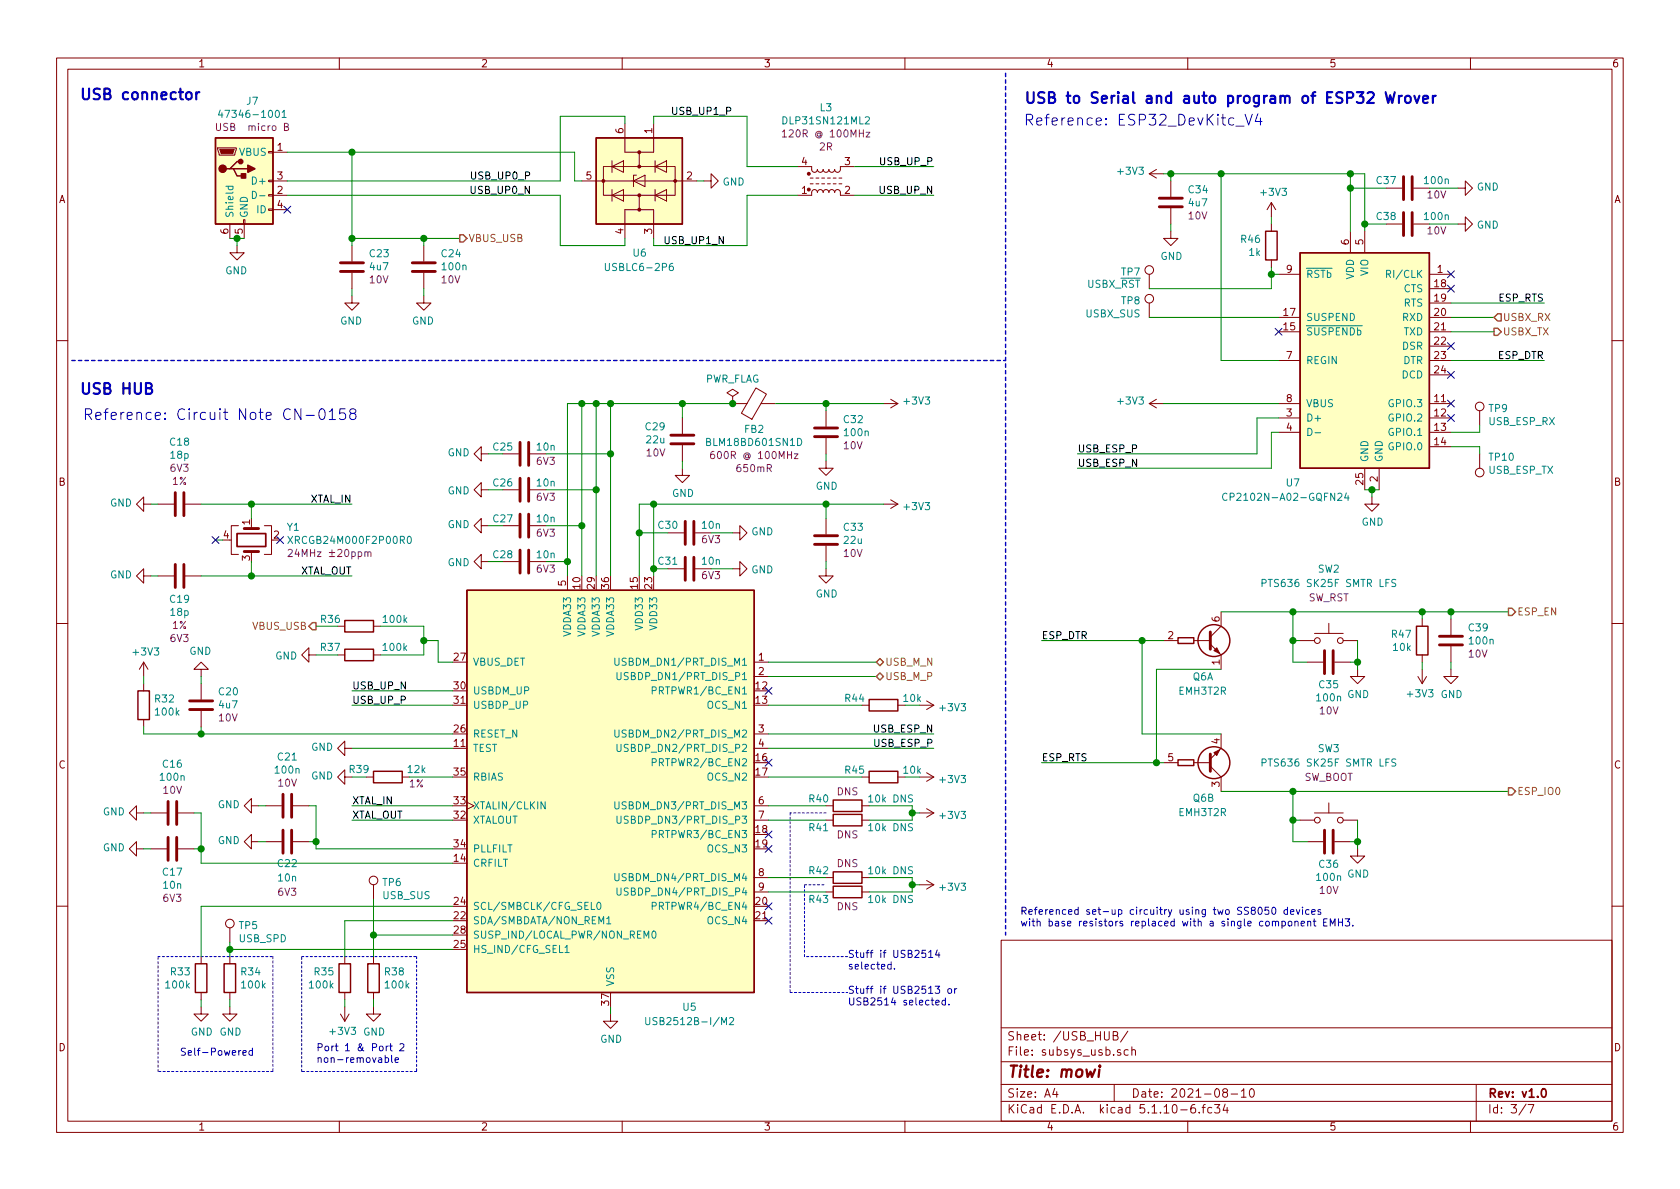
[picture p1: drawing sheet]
<svg xmlns="http://www.w3.org/2000/svg" width="297mm" height="210mm" viewBox="0 0 297 210" stroke-linecap="round" stroke-linejoin="round" font-family="sans-serif">
<defs><g id="words">
<text font-size="2.8" fill="#840000" x="178" y="190.5">Title: mowi</text>
<g font-size="2.7" fill="#0000c2">
<text x="14" y="17.7">USB connector</text>
<text x="181" y="18.3">USB to Serial and auto program of ESP32 Wrover</text>
<text x="181" y="22.2">Reference: ESP32_DevKitc_V4</text>
<text x="14" y="69.7">USB HUB</text>
<text x="14.6" y="74.3">Reference: Circuit Note CN-0158</text>
</g>
<g font-size="2.1" fill="#840000">
<text x="178" y="184">Sheet: /USB_HUB/</text>
<text x="178" y="186.7">File: subsys_usb.sch</text>
<text x="178" y="196.9">KiCad E.D.A. kicad 5.1.10-6.fc34</text>
<text x="178" y="194.1">Size: A4</text>
<text x="200" y="194.1">Date: 2021-08-10</text>
<text x="263" y="194.1">Rev: v1.0</text>
<text x="263" y="196.9">Id: 3/7</text>
</g>
<g font-size="1.8" fill="#840000">
<text x="35" y="11.9">1</text>
<text x="85" y="11.9">2</text>
<text x="135" y="11.9">3</text>
<text x="185" y="11.9">4</text>
<text x="235" y="11.9">5</text>
<text x="285" y="11.9">6</text>
<text x="110.2" y="23.6" transform="rotate(-90 110.2 23.6)">6</text>
<text x="115.3" y="23.6" transform="rotate(-90 115.3 23.6)">1</text>
<text x="49" y="26.7">1</text>
<text x="141.8" y="29.2">4</text>
<text x="149.4" y="29.2">3</text>
<text x="10.4" y="35.9">A</text>
<text x="49" y="34.3">2</text>
<text x="49" y="31.7">3</text>
<text x="103.7" y="31.7">5</text>
<text x="121.4" y="31.7">2</text>
<text x="141.8" y="34.3">1</text>
<text x="149.4" y="34.3">2</text>
<text x="285.4" y="35.9">A</text>
<text x="40.4" y="41.4" transform="rotate(-90 40.4 41.4)">6</text>
<text x="42.9" y="41.4" transform="rotate(-90 42.9 41.4)">5</text>
<text x="49" y="36.8">4</text>
<text x="110.2" y="41.4" transform="rotate(-90 110.2 41.4)">4</text>
<text x="115.3" y="41.4" transform="rotate(-90 115.3 41.4)">3</text>
<text x="238.5" y="43.3" transform="rotate(-90 238.5 43.3)">6</text>
<text x="241" y="43.3" transform="rotate(-90 241 43.3)">5</text>
<text x="227.5" y="48.3">9</text>
<text x="253.7" y="50.8">18</text>
<text x="253.7" y="53.3">19</text>
<text x="254.2" y="48.3">1</text>
<text x="227" y="58.4">15</text>
<text x="227" y="55.9">17</text>
<text x="253.7" y="55.9">20</text>
<text x="253.7" y="58.4">21</text>
<text x="227.5" y="63.5">7</text>
<text x="253.7" y="61">22</text>
<text x="253.7" y="63.5">23</text>
<text x="227.5" y="71.1">8</text>
<text x="253.7" y="71.1">11</text>
<text x="253.7" y="66">24</text>
<text x="227.5" y="73.7">3</text>
<text x="227.5" y="76.2">4</text>
<text x="253.7" y="73.7">12</text>
<text x="253.7" y="76.2">13</text>
<text x="253.7" y="78.7">14</text>
<text x="10.4" y="85.9">B</text>
<text x="241" y="85.7" transform="rotate(-90 241 85.7)">25</text>
<text x="243.6" y="85.2" transform="rotate(-90 243.6 85.2)">2</text>
<text x="285.4" y="85.9">B</text>
<text x="39.5" y="95.2">4</text>
<text x="44.2" y="92.8" transform="rotate(-90 44.2 92.8)">1</text>
<text x="48.4" y="95.2">2</text>
<text x="44.2" y="99.2" transform="rotate(-90 44.2 99.2)">3</text>
<text x="100.1" y="103.6" transform="rotate(-90 100.1 103.6)">5</text>
<text x="102.6" y="104.1" transform="rotate(-90 102.6 104.1)">10</text>
<text x="105.2" y="104.1" transform="rotate(-90 105.2 104.1)">29</text>
<text x="107.7" y="104.1" transform="rotate(-90 107.7 104.1)">36</text>
<text x="112.8" y="104.1" transform="rotate(-90 112.8 104.1)">15</text>
<text x="115.3" y="104.1" transform="rotate(-90 115.3 104.1)">23</text>
<text x="206.5" y="113">2</text>
<text x="215.6" y="110" transform="rotate(-90 215.6 110)">6</text>
<text x="80.3" y="116.8">27</text>
<text x="134.1" y="116.8">1</text>
<text x="134.1" y="119.4">2</text>
<text x="215.6" y="117.6" transform="rotate(-90 215.6 117.6)">1</text>
<text x="80.3" y="121.9">30</text>
<text x="80.3" y="124.5">31</text>
<text x="133.7" y="121.9">12</text>
<text x="133.7" y="124.5">13</text>
<text x="80.3" y="129.5">26</text>
<text x="134.1" y="129.5">3</text>
<text x="215.6" y="131.5" transform="rotate(-90 215.6 131.5)">4</text>
<text x="10.4" y="135.9">C</text>
<text x="80.3" y="132.1">11</text>
<text x="80.3" y="137.2">35</text>
<text x="133.7" y="134.6">16</text>
<text x="133.7" y="137.2">17</text>
<text x="134.1" y="132.1">4</text>
<text x="206.5" y="134.6">5</text>
<text x="285.4" y="135.9">C</text>
<text x="80.3" y="142.2">33</text>
<text x="134.1" y="142.2">6</text>
<text x="215.6" y="139.2" transform="rotate(-90 215.6 139.2)">3</text>
<text x="80.3" y="144.8">32</text>
<text x="80.3" y="149.9">34</text>
<text x="133.7" y="147.3">18</text>
<text x="133.7" y="149.9">19</text>
<text x="134.1" y="144.8">7</text>
<text x="80.3" y="152.4">14</text>
<text x="134.1" y="154.9">8</text>
<text x="80.3" y="160">24</text>
<text x="133.7" y="160">20</text>
<text x="134.1" y="157.5">9</text>
<text x="80.3" y="162.6">22</text>
<text x="80.3" y="167.6">25</text>
<text x="80.3" y="165.1">28</text>
<text x="133.7" y="162.6">21</text>
<text x="107.7" y="177.7" transform="rotate(-90 107.7 177.7)">37</text>
<text x="10.4" y="185.9">D</text>
<text x="285.4" y="185.9">D</text>
<text x="35" y="199.9">1</text>
<text x="85" y="199.9">2</text>
<text x="135" y="199.9">3</text>
<text x="185" y="199.9">4</text>
<text x="235" y="199.9">5</text>
<text x="285" y="199.9">6</text>
</g>
<g font-size="1.8" fill="#840084">
<text x="39" y="23.2">USB micro B</text>
<text x="139.3" y="24.3">120R @ 100MHz</text>
<text x="144.9" y="26.6">2R</text>
<text x="252.4" y="35.1">10V</text>
<text x="210.2" y="38.8">10V</text>
<text x="252.4" y="41.4">10V</text>
<text x="65.4" y="50.1">10V</text>
<text x="78.1" y="50.1">10V</text>
<text x="30.2" y="83.4">6V3</text>
<text x="94.9" y="82.2">6V3</text>
<text x="114.4" y="80.7">10V</text>
<text x="126.6" y="81.2">600R @ 100MHz</text>
<text x="130.5" y="83.5">650mR</text>
<text x="149.2" y="79.4">10V</text>
<text x="30.5" y="85.7">1%</text>
<text x="94.9" y="88.6">6V3</text>
<text x="94.9" y="94.9">6V3</text>
<text x="51.9" y="98.5">24MHz ±20ppm</text>
<text x="94.9" y="101.3">6V3</text>
<text x="124.2" y="96.1">6V3</text>
<text x="149.2" y="98.5">10V</text>
<text x="124.2" y="102.4">6V3</text>
<text x="231.3" y="106.3">SW_RST</text>
<text x="30.2" y="113.5">6V3</text>
<text x="30.5" y="111.2">1%</text>
<text x="259.7" y="116.3">10V</text>
<text x="38.7" y="127.6">10V</text>
<text x="233.4" y="126.3">10V</text>
<text x="28.9" y="140.4">10V</text>
<text x="49.2" y="139.1">10V</text>
<text x="72.4" y="139.2">1%</text>
<text x="148" y="140.6">DNS</text>
<text x="230.5" y="138.1">SW_BOOT</text>
<text x="148" y="148.3">DNS</text>
<text x="148" y="153.3">DNS</text>
<text x="28.9" y="159.5">6V3</text>
<text x="49.2" y="158.4">6V3</text>
<text x="148" y="161">DNS</text>
<text x="233.4" y="158.1">10V</text>
</g>
<g font-size="1.8" fill="#008484">
<text x="39.9" y="20.8">47346-1001</text>
<text x="43.7" y="18.5">J7</text>
<text x="138.8" y="22">DLP31SN121ML2</text>
<text x="145" y="19.7">L3</text>
<text x="42.3" y="27.6">VBUS</text>
<text x="44.9" y="32.6">D+</text>
<text x="127.8" y="32.8">GND</text>
<text x="197.8" y="30.9">+3V3</text>
<text x="210.2" y="34.2">C34</text>
<text x="223.1" y="34.6">+3V3</text>
<text x="243.5" y="32.6">C37</text>
<text x="252" y="32.6">100n</text>
<text x="261.1" y="33.7">GND</text>
<text x="41.3" y="38.6" transform="rotate(-90 41.3 38.6)">Shield</text>
<text x="43.8" y="38.6" transform="rotate(-90 43.8 38.6)">GND</text>
<text x="45.5" y="37.7">ID</text>
<text x="210.3" y="36.5">4u7</text>
<text x="243.5" y="38.9">C38</text>
<text x="252" y="38.9">100n</text>
<text x="261.1" y="40.4">GND</text>
<text x="65.4" y="45.5">C23</text>
<text x="65.5" y="47.8">4u7</text>
<text x="78.1" y="45.5">C24</text>
<text x="78.3" y="47.8">100n</text>
<text x="107.6" y="47.9">USBLC6-2P6</text>
<text x="112" y="45.4">U6</text>
<text x="205.2" y="46">GND</text>
<text x="219.5" y="42.9">R46</text>
<text x="220.9" y="45.3">1k</text>
<text x="39.8" y="48.5">GND</text>
<text x="192.2" y="50.9">USBX_RST</text>
<text x="198.3" y="53.8">TP8</text>
<text x="198.3" y="48.7">TP7</text>
<text x="230.9" y="49.1">RSTb</text>
<text x="239.4" y="49.4" transform="rotate(-90 239.4 49.4)">VDD</text>
<text x="241.9" y="48.8" transform="rotate(-90 241.9 48.8)">VIO</text>
<text x="245.8" y="49.1">RI/CLK</text>
<text x="248.2" y="51.7">CTS</text>
<text x="60.1" y="57.4">GND</text>
<text x="72.8" y="57.4">GND</text>
<text x="192" y="56.1">USBX_SUS</text>
<text x="230.9" y="59.3">SUSPENDb</text>
<text x="230.9" y="56.8">SUSPEND</text>
<text x="248" y="56.8">RXD</text>
<text x="248.2" y="54.2">RTS</text>
<text x="248.2" y="59.3">TXD</text>
<text x="230.9" y="64.4">REGIN</text>
<text x="248" y="61.8">DSR</text>
<text x="248.1" y="64.4">DTR</text>
<text x="124.6" y="67.7">PWR_FLAG</text>
<text x="160" y="71.5">+3V3</text>
<text x="197.8" y="71.5">+3V3</text>
<text x="247.9" y="66.9">DCD</text>
<text x="114.2" y="76.1">C29</text>
<text x="131.7" y="76.5">FB2</text>
<text x="149.3" y="74.8">C32</text>
<text x="149.4" y="77.1">100n</text>
<text x="230.9" y="74.5">D+</text>
<text x="230.9" y="72">VBUS</text>
<text x="245.8" y="72">GPIO.3</text>
<text x="245.8" y="74.5">GPIO.2</text>
<text x="245.8" y="77.1">GPIO.1</text>
<text x="263.2" y="75.2">USB_ESP_RX</text>
<text x="263.3" y="72.9">TP9</text>
<text x="30.1" y="78.8">C18</text>
<text x="30.2" y="81.1">18p</text>
<text x="79.1" y="80.7">GND</text>
<text x="87.3" y="79.7">C25</text>
<text x="95" y="79.7">10n</text>
<text x="114.4" y="78.4">22u</text>
<text x="125.3" y="78.9">BLM18BD601SN1D</text>
<text x="241.9" y="81.8" transform="rotate(-90 241.9 81.8)">GND</text>
<text x="244.5" y="81.8" transform="rotate(-90 244.5 81.8)">GND</text>
<text x="245.8" y="79.6">GPIO.0</text>
<text x="263.2" y="83.8">USB_ESP_TX</text>
<text x="263.4" y="81.5">TP10</text>
<text x="19.5" y="89.6">GND</text>
<text x="79.1" y="87.4">GND</text>
<text x="87.3" y="86">C26</text>
<text x="95" y="86">10n</text>
<text x="118.8" y="87.9">GND</text>
<text x="144.2" y="86.6">GND</text>
<text x="217.8" y="88.6">CP2102N-A02-GQFN24</text>
<text x="227.5" y="86">U7</text>
<text x="50.8" y="93.9">Y1</text>
<text x="79.1" y="93.4">GND</text>
<text x="87.3" y="92.4">C27</text>
<text x="95" y="92.4">10n</text>
<text x="116.5" y="93.5">C30</text>
<text x="124.2" y="93.5">10n</text>
<text x="132.8" y="94.7">GND</text>
<text x="149.3" y="93.9">C33</text>
<text x="160" y="90.2">+3V3</text>
<text x="240.7" y="93">GND</text>
<text x="51.7" y="96.2">XRCGB24M000F2P00R0</text>
<text x="79.1" y="100.1">GND</text>
<text x="87.3" y="98.7">C28</text>
<text x="95" y="98.7">10n</text>
<text x="116.5" y="99.9">C31</text>
<text x="124.2" y="99.9">10n</text>
<text x="132.8" y="101.4">GND</text>
<text x="149.3" y="96.2">22u</text>
<text x="233" y="101.3">SW2</text>
<text x="19.5" y="102.3">GND</text>
<text x="30.1" y="106.6">C19</text>
<text x="144.2" y="105.7">GND</text>
<text x="224.1" y="103.8">PTS636 SK25F SMTR LFS</text>
<text x="30.2" y="108.9">18p</text>
<text x="56.8" y="110.2">R36</text>
<text x="67.9" y="110.2">100k</text>
<text x="101" y="112.4" transform="rotate(-90 101 112.4)">VDDA33</text>
<text x="103.5" y="112.4" transform="rotate(-90 103.5 112.4)">VDDA33</text>
<text x="106" y="112.4" transform="rotate(-90 106 112.4)">VDDA33</text>
<text x="108.6" y="112.4" transform="rotate(-90 108.6 112.4)">VDDA33</text>
<text x="113.7" y="111.1" transform="rotate(-90 113.7 111.1)">VDD33</text>
<text x="116.2" y="111.1" transform="rotate(-90 116.2 111.1)">VDD33</text>
<text x="246.1" y="112.8">R47</text>
<text x="259.7" y="111.7">C39</text>
<text x="259.9" y="114">100n</text>
<text x="23.7" y="115.9">+3V3</text>
<text x="33.5" y="115.8">GND</text>
<text x="48.7" y="116.6">GND</text>
<text x="56.8" y="115.1">R37</text>
<text x="67.9" y="115.1">100k</text>
<text x="83.6" y="117.7">VBUS_DET</text>
<text x="109.9" y="117.7">USBDM_DN1/PRT_DIS_M1</text>
<text x="246.4" y="115.1">10k</text>
<text x="27.5" y="124.2">R32</text>
<text x="38.8" y="123">C20</text>
<text x="38.8" y="125.3">4u7</text>
<text x="83.6" y="122.8">USBDM_UP</text>
<text x="83.6" y="125.3">USBDP_UP</text>
<text x="110.5" y="120.3">USBDP_DN1/PRT_DIS_P1</text>
<text x="116.2" y="122.8">PRTPWR1/BC_EN1</text>
<text x="125.2" y="125.3">OCS_N1</text>
<text x="149.5" y="124.1">R44</text>
<text x="166.3" y="125.8">+3V3</text>
<text x="208.5" y="122.9">EMH3T2R</text>
<text x="210.9" y="120.3">Q6A</text>
<text x="232.9" y="124">100n</text>
<text x="233.3" y="121.7">C35</text>
<text x="238.2" y="123.4">GND</text>
<text x="249" y="123.3">+3V3</text>
<text x="254.7" y="123.4">GND</text>
<text x="27.6" y="126.5">100k</text>
<text x="83.6" y="130.4">RESET_N</text>
<text x="109.9" y="130.4">USBDM_DN2/PRT_DIS_M2</text>
<text x="28.9" y="135.8">C16</text>
<text x="48.8" y="136.8">100n</text>
<text x="49.2" y="134.5">C21</text>
<text x="55" y="137.8">GND</text>
<text x="55" y="132.8">GND</text>
<text x="61.8" y="136.7">R39</text>
<text x="72.2" y="136.7">12k</text>
<text x="83.6" y="133">TEST</text>
<text x="110.5" y="133">USBDP_DN2/PRT_DIS_P2</text>
<text x="116.2" y="135.5">PRTPWR2/BC_EN2</text>
<text x="149.5" y="136.8">R45</text>
<text x="224.1" y="135.6">PTS636 SK25F SMTR LFS</text>
<text x="233" y="133">SW3</text>
<text x="28.5" y="138.1">100n</text>
<text x="38.5" y="142.9">GND</text>
<text x="83.6" y="143.1">XTALIN/CLKIN</text>
<text x="83.6" y="138">RBIAS</text>
<text x="109.9" y="143.1">USBDM_DN3/PRT_DIS_M3</text>
<text x="125.2" y="138">OCS_N2</text>
<text x="143.1" y="141.9">R40</text>
<text x="153.9" y="141.9">10k DNS</text>
<text x="166.3" y="138.5">+3V3</text>
<text x="211" y="141.8">Q6B</text>
<text x="18.2" y="144.2">GND</text>
<text x="38.5" y="149.3">GND</text>
<text x="83.6" y="145.7">XTALOUT</text>
<text x="110.5" y="145.7">USBDP_DN3/PRT_DIS_P3</text>
<text x="116.2" y="148.2">PRTPWR3/BC_EN3</text>
<text x="143.1" y="147">R41</text>
<text x="153.9" y="147">10k DNS</text>
<text x="166.3" y="144.8">+3V3</text>
<text x="208.5" y="144.3">EMH3T2R</text>
<text x="18.2" y="150.5">GND</text>
<text x="28.9" y="154.9">C17</text>
<text x="49.2" y="153.3">C22</text>
<text x="49.3" y="155.9">10n</text>
<text x="83.6" y="153.3">CRFILT</text>
<text x="83.6" y="150.7">PLLFILT</text>
<text x="109.9" y="155.8">USBDM_DN4/PRT_DIS_M4</text>
<text x="125.2" y="150.7">OCS_N3</text>
<text x="143.1" y="154.6">R42</text>
<text x="153.9" y="154.6">10k DNS</text>
<text x="232.9" y="155.8">100n</text>
<text x="233.3" y="153.5">C36</text>
<text x="238.2" y="155.2">GND</text>
<text x="29" y="157.2">10n</text>
<text x="67.7" y="156.7">TP6</text>
<text x="67.7" y="159">USB_SUS</text>
<text x="83.6" y="160.9">SCL/SMBCLK/CFG_SEL0</text>
<text x="110.5" y="158.4">USBDP_DN4/PRT_DIS_P4</text>
<text x="116.2" y="160.9">PRTPWR4/BC_EN4</text>
<text x="143.1" y="159.7">R43</text>
<text x="153.9" y="159.7">10k DNS</text>
<text x="166.3" y="157.5">+3V3</text>
<text x="42.3" y="164.3">TP5</text>
<text x="42.3" y="166.6">USB_SPD</text>
<text x="83.6" y="163.4">SDA/SMBDATA/NON_REM1</text>
<text x="83.6" y="166">SUSP_IND/LOCAL_PWR/NON_REM0</text>
<text x="125.2" y="163.4">OCS_N4</text>
<text x="30.3" y="172.5">R33</text>
<text x="42.7" y="172.5">R34</text>
<text x="55.7" y="172.5">R35</text>
<text x="68.1" y="172.5">R38</text>
<text x="83.6" y="168.5">HS_IND/CFG_SEL1</text>
<text x="29.4" y="174.8">100k</text>
<text x="42.8" y="174.8">100k</text>
<text x="54.8" y="174.8">100k</text>
<text x="68.2" y="174.8">100k</text>
<text x="108.6" y="174.5" transform="rotate(-90 108.6 174.5)">VSS</text>
<text x="120.8" y="178.7">U5</text>
<text x="33.7" y="183.1">GND GND</text>
<text x="58.5" y="183">+3V3</text>
<text x="64.2" y="183.1">GND</text>
<text x="106.1" y="184.4">GND</text>
<text x="115.4" y="181.3">USB2512B-I/M2</text>
</g>
<g font-size="1.8">
<text x="119.2" y="20.3">USB_UP1_P</text>
<text x="155.8" y="29.2">USB_UP_P</text>
<text x="83.6" y="34.3">USB_UP0_N</text>
<text x="83.7" y="31.7">USB_UP0_P</text>
<text x="155.7" y="34.3">USB_UP_N</text>
<text x="117.9" y="43.2">USB_UP1_N</text>
<text x="265" y="53.3">ESP_RTS</text>
<text x="264.9" y="63.5">ESP_DTR</text>
<text x="190.5" y="80">USB_ESP_P</text>
<text x="190.5" y="82.5">USB_ESP_N</text>
<text x="54.9" y="88.9">XTAL_IN</text>
<text x="52.9" y="101.6">XTAL_OUT</text>
<text x="184.1" y="113">ESP_DTR</text>
<text x="62.2" y="124.5">USB_UP_P</text>
<text x="62.2" y="121.9">USB_UP_N</text>
<text x="154.6" y="129.5">USB_ESP_N</text>
<text x="154.7" y="132.1">USB_ESP_P</text>
<text x="184.1" y="134.6">ESP_RTS</text>
<text x="62.2" y="142.2">XTAL_IN</text>
<text x="62.2" y="144.8">XTAL_OUT</text>
</g>
<g font-size="1.8" fill="#848400">
<text x="82.8" y="42.8">VBUS_USB</text>
<text x="265.7" y="56.8">USBX_RX</text>
<text x="265.7" y="59.3">USBX_TX</text>
<text x="44.7" y="111.4">VBUS_USB</text>
<text x="268.2" y="108.8">ESP_EN</text>
<text x="156.5" y="117.7">USB_M_N</text>
<text x="156.5" y="120.3">USB_M_P</text>
<text x="268.2" y="140.6">ESP_IO0</text>
</g>
<g font-size="1.8" fill="#008400">
<text x="159.8" y="124.1">10k</text>
<text x="159.8" y="136.8">10k</text>
</g>
<g font-size="1.8" fill="#0000c2">
<text x="180.3" y="161.8">Referenced set-up circuitry using two SS8050 devices</text>
<text x="180.3" y="163.8">with base resistors replaced with a single component EMH3.</text>
<text x="149.9" y="169.4">Stuff if USB2514</text>
<text x="149.9" y="171.4">selected.</text>
<text x="149.9" y="175.7">Stuff if USB2513 or</text>
<text x="149.9" y="177.8">USB2514 selected.</text>
<text x="55.9" y="185.9">Port 1 &amp; Port 2</text>
<text x="31.7" y="186.7">Self-Powered</text>
<text x="55.9" y="188">non-removable</text>
</g>
</g></defs>
<g fill="none" stroke="#840000" stroke-width=".18">
<path d="M10 10.3h277v189.9h-277zM12 12.2h273v186.1h-273zM60 10.3v1.9M110 10.3v1.9M160 10.3v1.9M210 10.3v1.9M260 10.3v1.9M38.5 26.2h3.3v.2l-.3 1h-2.8zM40.6 39.6v2.6M43.1 38.9h.2v.7h-.2zM43.2 39.6v2.6M47.5 37h.8v.2h-.8z"/>
<path d="M47.5 34.4h.8v.3h-.8zM47.5 31.9h.8v.2h-.8zM47.5 26.8h.8v.2h-.8zM48.3 26.9h2.5M48.3 34.5h2.5M48.3 32h2.5M48.3 37.1h2.5M102.9 32h20.3M106.7 29.5h12.7v5h-12.7zM108.2 29.5l2-1.1v2.1zM108.2 34.5l2-1v2.1zM108.2 28.4v2.1"/>
<path d="M108.2 33.5v2.1M110.5 21.8v5.1h2.5v2.6M112 32l2-1v2zM112.5 31h-.5v2M113 34.5v2.6h-2.5v5.1M113 37.1h2.6v5.1M115.6 21.8v5.1h-2.6M115.8 29.5l2.1-1.1v2.1zM115.8 34.5l2.1-1v2.1zM115.8 28.4v2.1M115.8 33.5v2.1M124.5 32h1.2v1.3l1.3-1.3-1.3-1.3v1.3"/>
<path d="M141 29.5h2.5v.6l.4 .4 .4-.1 .2-.4 .1 .3 .4 .2 .3-.1 .2-.4 .1 .3 .4 .2 .4-.1 .2-.4 .3 .4h.5l.2-.4 .2 .3 .4 .2 .4-.4v-.6h2.5M141 34.5h2.5v-.6l.4-.4 .4 .1 .2 .4 .2-.3 .2-.2 .5 .1 .1 .4 .2-.3 .2-.2 .5 .1 .2 .4 .1-.3 .3-.2 .4 .1 .2 .4 .2-.4 .4-.1 .4 .4v.6h2.5M143.3 31.5h.5M143.3 32.5h.5M144.3 31.5h.5M144.3 32.5h.5M145.3 31.5h.5M145.3 32.5h.5M146.3 31.5h.5M146.3 32.5h.5M147.3 31.5h.5M147.3 32.5h.5"/>
<path d="M148.3 31.5h.5M148.3 32.5h.5M203.2 30.7l1.3 .8M203.2 30.7h2.5M204.5 30l-1.3 .7M207 32v2.8M207 36.8v2.8M224.8 35.8l-.8 1.3M224.8 35.8v2.5M224.8 39.6v1.3M224.8 35.8l.8 1.3M245.1 39.6h2.8"/>
<path d="M245.1 33.3h2.8M249.9 39.6h2.8M249.9 33.3h2.8M257.8 33.3h1.3v-1.3l1.2 1.3-1.2 1.2v-1.2M257.8 39.6h1.3v1.3l1.2-1.3-1.2-1.3v1.3M41.9 43.4v1.3h-1.3l1.3 1.3 1.3-1.3h-1.3M62.2 52.3v1.3h-1.2l1.2 1.3 1.3-1.3h-1.3M62.2 43.4v2.8M62.2 48.3v2.7M74.9 52.3v1.3h-1.2l1.2 1.3 1.3-1.3h-1.3M74.9 43.4v2.8M74.9 48.3v2.7"/>
<path d="M203.2 48.5v2.5M203.2 53.6v2.5M207 40.9v1.3h1.3l-1.3 1.2-1.3-1.2h1.3M224.8 46v1.2M226.1 48.5h3.8M226.1 58.7h3.8M226.1 56.1h3.8M238.8 40.9v3.8M241.3 40.9v3.8M252.7 48.5h3.8M252.7 58.7h3.8M252.7 56.1h3.8"/>
<path d="M252.7 51h3.8M252.7 53.6h3.8M10 60.2h2M120.6 73.9v2.8M120.6 78.7v2.8M129.5 70.1l1.1-.6-1.1-.7-1 .7 1 .6v1.3M129.5 71.4h.1M129.5 71.4h2.6M133.7 68.6l1.8 1.1-2.6 4.4-1.8-1zM134.6 71.4h2.6M146 72.6v2.8M146 77.5v2.8"/>
<path d="M156.2 71.4h2.5M157.5 70.6l1.2 .8M158.7 71.4l-1.2 .7M203.2 71.4h2.5M203.2 71.4l1.3 .7M204.5 70.6l-1.3 .8M226.1 71.4h3.8M226.1 73.9h3.8M226.1 76.4h3.8M226.1 63.7h3.8M252.7 71.4h3.8M252.7 73.9h3.8"/>
<path d="M252.7 76.4h3.8M252.7 79h3.8M252.7 61.2h3.8M252.7 63.7h3.8M252.7 66.3h3.8M261.6 72.6v2.6M285 60.2h2M25.4 89.1v1.3l-1.3-1.3 1.3-1.2v1.2h1.3M27.9 89.1h2.8M32.8 89.1h2.8M42.2 93h-1.3v5h1.3M44.4 93v.5"/>
<path d="M44.4 97.5v.5M46.7 93h1.3v5h-1.3M85.1 93v1.2l-1.3-1.2 1.3-1.3v1.3h1.3M85.1 99.3v-1.3l-1.3 1.3 1.3 1.3v-1.3h1.3M85.1 80.3v1.2l-1.3-1.2 1.3-1.3v1.3h1.3M85.1 86.6v-1.3l-1.3 1.3 1.3 1.3v-1.3h1.3M88.9 99.3h2.8M88.9 93h2.8M88.9 80.3h2.8M88.9 86.6h2.8M93.7 99.3h2.8M93.7 93h2.8"/>
<path d="M93.7 80.3h2.8M93.7 86.6h2.8M118.1 94.2h2.8M120.6 82.8v1.3h1.3l-1.3 1.2-1.2-1.2h1.2M122.9 94.2h2.8M129.5 94.2h1.3v-1.2l1.3 1.2-1.3 1.3v-1.3M146 81.5v1.3h1.3l-1.3 1.3-1.2-1.3h1.2M146 91.7v2.8M146 96.5v2.8M156.2 89.1h2.5M157.5 88.4l1.2 .7M158.7 89.1l-1.2 .8"/>
<path d="M241.3 82.8v3.8M242.6 87.9v1.2h1.2l-1.2 1.3-1.3-1.3h1.3M243.8 82.8v3.8M261.6 80.3v2.5M10 110.3h2M25.4 101.8v1.3l-1.3-1.3 1.3-1.2v1.2h1.3M25.4 117.1l-.8 1.3M25.4 117.1v2.5M25.4 117.1l.8 1.3M27.9 101.8h2.8M32.8 101.8h2.8M35.6 118.4h1.2l-1.2-1.3-1.3 1.3h1.3v1.2"/>
<path d="M54.6 115.8v-1.3l-1.3 1.3 1.3 1.3v-1.3h1.3M59.7 110.7h1.3M59.7 115.8h1.3M66 110.7h1.3M66 115.8h1.3M100.3 101.8v2.6M118.1 100.6h2.8M122.9 100.6h2.8M129.5 100.6h1.3v1.2l1.3-1.2-1.3-1.3v1.3M133.3 117.1h2.6M133.3 119.6h2.6M146 100.6v1.2h1.3l-1.3 1.3-1.2-1.3h1.2"/>
<path d="M205.7 113.3h2.6M211.1 113.3h2.9M214 113.9l1.9 1.9v2.6M215.9 108.2v2.5l-1.9 1.9M229.9 113.3h2.5M231.1 117.1h2.8M232.4 112h5.1M234.9 110.2v1.8M236 117.1h2.8M237.5 113.3h2.5M240 118.4v1.2h1.3l-1.3 1.3-1.2-1.3h1.2M250.7 119.6l.8 1.3"/>
<path d="M251.5 109.5v1.2M251.5 115.8v1.3M251.5 118.4v2.5M252.2 119.6l-.7 1.3M256.5 118.4v1.2h1.3l-1.3 1.3-1.2-1.3h1.2M256.5 109.5v2.8M256.5 114.3v2.8M285 110.3h2M25.4 120.9v1.3M25.4 127.2v1.3M35.6 120.9v2.8M35.6 125.7v2.8"/>
<path d="M61 137.4v1.3l-1.3-1.3 1.3-1.3v1.3h1.2M61 132.3v1.3l-1.3-1.3 1.3-1.2v1.2h1.2M64.8 137.4h1.2M71.1 137.4h1.3M133.3 129.8h2.6M133.3 132.3h2.6M152.4 137.4h1.3M152.4 124.7h1.3M158.7 137.4h1.3M158.7 124.7h1.3M162.6 137.4h2.5M162.6 124.7h2.5"/>
<path d="M163.8 123.9l1.3 .8M163.8 136.6l1.3 .8M165.1 124.7l-1.3 .8M165.1 137.4l-1.3 .8M205.7 134.9h2.6M211.1 134.9h2.9M214 135.5l1.9 1.9v2.5M215.9 129.8v2.5l-1.9 1.9M24.1 143.8v1.2l-1.2-1.2 1.2-1.3v1.3h1.3M24.1 150.1v1.3l-1.2-1.3 1.2-1.3v1.3h1.3M26.7 143.8h2.8M26.7 150.1h2.8"/>
<path d="M31.5 143.8h2.8M31.5 150.1h2.8M44.4 148.8v1.3l-1.2-1.3 1.2-1.2v1.2h1.3M44.4 142.5v1.3l-1.2-1.3 1.2-1.3v1.3h1.3M47 142.5h2.8M47 148.8h2.8M51.8 142.5h2.8M51.8 148.8h2.8M66 156.5v2.5M82.5 141.9l1.3 .6-1.3 .6M133.3 142.5h2.6M133.3 145h2.6"/>
<path d="M133.3 155.2h2.6M133.3 157.7h2.6M146 142.5h1.3M146 145h1.3M146 155.2h1.3M146 157.7h1.3M152.4 142.5h1.3M152.4 145h1.3M152.4 155.2h1.3M152.4 157.7h1.3M162.6 156.5h2.5M162.6 143.8h2.5"/>
<path d="M163.8 155.7l1.3 .8M163.8 143l1.3 .8M165.1 156.5l-1.3 .7M165.1 143.8l-1.3 .7M229.9 145h2.5M231.1 148.8h2.8M232.4 143.8h5.1M234.9 142v1.8M236 148.8h2.8M237.5 145h2.5M240 150.1v1.3h1.3l-1.3 1.2-1.2-1.2h1.2M10 160.2h2"/>
<path d="M35.6 178v1.3h1.2l-1.2 1.3-1.3-1.3h1.3M35.6 169.2v1.2M35.6 175.5v1.3M40.6 178v1.3h1.3l-1.3 1.3-1.2-1.3h1.2M40.6 164.1v2.5M40.6 169.2v1.2M40.6 175.5v1.3M60.2 179.3l.8 1.3M61 169.2v1.2M61 175.5v1.3M61 178v2.6M61.7 179.3l-.7 1.3"/>
<path d="M66 178v1.3h1.3l-1.3 1.3-1.2-1.3h1.2M66 169.2v1.2M66 175.5v1.3M107.9 179.3v1.3h1.3l-1.3 1.3-1.2-1.3h1.2M177 166.3h108v32h-108zM285 160.2h2M60 198.3v1.9M110 198.3v1.9M160 198.3v1.9M177 194.8h108M177 191.8h108M177 187.8h108"/>
<path d="M177 181.8h108M186.5 192.5l-.4 1h1M186.8 193v1M196.8 183.1l.8-.1v-.3l-.1-.2-.7-.1v1.5h.6l.3-.3a.41 .41 0 0 0-.4-.5M197 191.8v3M198.1 185.7l-.3-.1-.2 .2v.2l.5 .2v.3h-.5M199.4 182.3l-1.3 2M199.5 185.7l-.4-.1-.3 .3v.6l.3 .1 .4-.1M200.1 185.7l.2-.1 .4 .1 .1 .9M200.1 185.1v1.5M208.8 196.3h1.1M210 198.3v1.9"/>
<path d="M211.3 195.3a.59 .59 0 0 0-.8 .7v.5l.2 .2 .4 .1 .2-.1 .1-.5-.1-.2-.5-.1-.3 .3M212 196.7v.1M212.5 195.8h.6M213.1 195.3l-.3 .2v1.3M214.2 195.9l-.4-.1-.3 .3 .2 .6h.5M214.8 195.3h.9l-.5 .6 .4 .1v.7l-.2 .1-.6-.1M216.5 193.2l-.3-.3 .1-.2a.48 .48 0 0 1 .6-.1l.1 .2-.1 .3-.6 .1a.48 .48 0 0 0 0 .7l.2 .1 .5-.1v-.4l-.2-.3M216.6 195.2l-.3 1.1h.9M217 195.8v1M217.7 193.5h1.1M219.5 193l.4-.5v1.5M219.5 194h.8"/>
<path d="M221.1 192.6l.2-.1a.8 .8 0 0 1 .5 .8 .8 .8 0 0 1-.5 .7 1 1 0 0 1-.2-1.4zM260 198.3v1.9M261 191.8v6.5M269.8 195.2l-1.2 2M270.2 195.3h1l-.6 1.5"/>
<circle cx="203.2" cy="47.7" r=".76"/>
<circle cx="203.2" cy="52.8" r=".76"/>
<circle cx="261.6" cy="71.9" r=".76"/>
<circle cx="261.6" cy="83.6" r=".76"/>
<circle cx="232.9" cy="113.3" r=".51"/>
<circle cx="237" cy="113.3" r=".51"/>
<circle cx="66" cy="155.7" r=".76"/>
<circle cx="232.9" cy="145" r=".51"/>
<circle cx="237" cy="145" r=".51"/>
<circle cx="40.6" cy="163.3" r=".76"/>
</g>
<path d="M41.9 94.4h5.1v2.2h-5.1zM272.7 192.7l.2-.2a.81 .81 0 0 1 .6 .6 .81 .81 0 0 1-.3 .8l-.2 .1a.79 .79 0 0 1-.3-1.3z" fill="none" stroke="#840000" stroke-width=".3"/>
<path d="M194.4 189.1l-.2 1.3M194.5 188.4l-.1 .1 .1 .1 .1-.1-.1-.1v.2" fill="none" stroke="#840000" stroke-width=".41"/>
<g fill="none" stroke="#840000" stroke-width=".51">
<path d="M205 36.6h4M205 35h4M248.2 31.2v4.1M248.2 37.6v4.1M249.7 31.2v4.1M249.7 37.6v4.1M60.2 46.5h4.1M60.2 48h4.1M72.9 46.5h4.1M72.9 48h4.1M91.9 78.2v4.1M93.5 78.2v4.1"/>
<path d="M118.6 78.5h4.1M118.6 77h4.1M144 77.2h4.1M144 75.7h4.1M31 87.1v4.1M31 99.8v4.1M32.5 87.1v4.1M32.5 99.8v4.1M43.2 93.5h2.5M43.2 97.5h2.5M91.9 84.6v4M91.9 90.9v4.1"/>
<path d="M91.9 97.3v4M93.5 84.6v4M93.5 90.9v4.1M93.5 97.3v4M121.2 92.2v4.1M121.2 98.5v4.1M122.7 92.2v4.1M122.7 98.5v4.1M144 96.3h4.1M144 94.7h4.1M214 111.8v3M234.2 115.1v4"/>
<path d="M235.7 115.1v4M254.5 114h4.1M254.5 112.5h4.1M33.5 123.9h4.1M33.5 125.5h4.1M214 133.3v3.1M29.7 141.7v4.1M29.7 148.1v4M31.2 141.7v4.1M31.2 148.1v4M50 140.5v4M50 146.8v4.1"/>
<path d="M51.6 140.5v4M51.6 146.8v4.1M234.2 146.8v4.1M235.7 146.8v4.1"/>
</g>
<g fill="none" stroke="#840000" stroke-width=".25">
<path d="M38.1 24.4h10.2v15.2h-10.2zM40.6 29.8h.7l.6 1.3h1.3M41.3 29.8h2.5M42.5 28.6h-.6l-1.3 1.2h-.6M105.4 24.4h15.2v15.2h-15.2zM223.8 40.9h2v5.1h-2zM229.9 44.7h22.8v38.1h-22.8zM61 109.7h5v2.1h-5zM61 114.8h5v2h-5zM82.5 104.4h50.8v71.1h-50.8zM208.3 112.8h2.8v1h-2.8zM250.4 110.7h2.1v5.1h-2.1z"/>
<path d="M24.4 122.2h2v5h-2zM66 136.4h5.1v2h-5.1zM153.7 136.4h5v2h-5zM153.7 123.7h5v2h-5zM208.3 134.4h2.8v1h-2.8zM147.3 154.2h5.1v2h-5.1zM147.3 156.7h5.1v2h-5.1zM147.3 144h5.1v2h-5.1zM147.3 141.5h5.1v2h-5.1zM34.5 170.4h2.1v5.1h-2.1zM39.6 170.4h2.1v5.1h-2.1zM59.9 170.4h2.1v5.1h-2.1z"/>
<path d="M65 170.4h2.1v5.1h-2.1z"/>
<circle cx="214.6" cy="113.3" r="2.82"/>
<circle cx="214.6" cy="134.9" r="2.82"/>
</g>
<g fill="none" stroke="#008484" stroke-width=".18">
<path d="M38.9 19.5l-.3 .8h.8M39.2 19.9v.9M49.9 19.9l.3-.4v1.3M39.9 32.9h1.3M40.4 32.9v.4l.2 .2 .5-.1v-.5M44.6 33.8a.64 .64 0 0 1 .7 .7 .64 .64 0 0 1-.7 .6zM45.9 34.6h1M49.9 20.8h.7M153 20.8l.5-.2 .2 .2v.2v.2l-.8 .7h.8M107 46.6v1l.3 .2h.3l.1-.2v-1M118.9 46.6l-.4 .1-.2 .4 .1 .6 .2 .1h.3l.2-.2-.2-.5h-.3l-.3 .2M245.2 48.5l.6-.1v-.5l-.2-.1h-.4v1.3"/>
<path d="M141 77.5a.64 .64 0 0 1 .8 .7 .64 .64 0 0 1-.8 .6zM231.2 75.7a.64 .64 0 0 1 .8 .7 .64 .64 0 0 1-.8 .6zM232.5 76.5h1M50.9 94.8l.8 1.3M51.7 94.8l-.8 1.3M72.1 95l.2-.2a.67 .67 0 0 1 .4 .7 .67 .67 0 0 1-.4 .6l-.2-.1-.1-.4zM216.9 87.3a.6 .6 0 0 0-.8 .5 .6 .6 0 0 0 .6 .7l.2-.1M238 87.2l-.3 .9h.8M238.4 87.6v.9M108.7 116.4v1l.3 .2h.3l.1-.2v-1M109.1 118.9v1.1l.2 .2h.3l.2-.2v-1.1M223.1 103.1h.6l.2-.2-.1-.3-.2-.1h-.5v1.2"/>
<path d="M246.8 102.5h-.5l-.2 .1 .1 .4 .5 .2 .1 .3-.2 .2h-.5M108.7 129.1v1l.3 .2h.3l.1-.2v-1M109.1 131.6v1.1l.2 .2h.3l.2-.2v-1.1M115.3 122.1h.6l.1-.5-.2-.1h-.5v1.2M115.3 134.8h.6l.1-.5-.2-.1h-.5v1.2M223.1 134.9l.6-.1 .2-.2-.1-.3-.2-.1h-.5v1.3M246.8 134.3l-.5-.1-.2 .1 .1 .5 .5 .2 .1 .2-.2 .3-.5-.1M96.4 141.8v1.2l-.7-1.2v1.2M104.5 159.6v1.2h.7M105.6 159.7l.2-.1a.67 .67 0 0 1 .5 .6 .67 .67 0 0 1-.5 .6l-.3-.5zM108.7 141.8v1l.3 .2h.3l.1-.2v-1M108.7 154.5v1l.3 .2h.3l.1-.2v-1"/>
<path d="M109.1 144.3v1.1l.2 .2h.3l.2-.2v-1.1M109.1 157v1.1l.2 .2h.3l.2-.2v-1.1M115.3 147.5h.6l.1-.5-.2-.1h-.5v1.2M99.9 167.5l.4-.3v1.2M99.9 168.4h.7M107.3 162.5l.3-.4v1.3M107.3 163.4h.7M113.9 165.9v-1.3l.4 1 .4-1v1.3M114.2 179.9v1.1l.2 .2 .4-.1 .1-.1v-1.1M115.3 160.2h.6l.1-.5-.2-.1h-.5v1.2M115.4 164.8l.2-.2a.69 .69 0 0 1 .4 .7 .69 .69 0 0 1-.4 .6l-.3-.2v-.3zM129 180.1l.5-.2 .2 .4-.8 .9h.8"/>
</g>
<path d="M38.3 21.8v1.1l.2 .2h.3l.2-.2v-1.1M50.3 22.4h.6l.1-.2-.1-.3-.6-.1v1.3h.5l.2-.1v-.3l-.3-.3M138.3 23.3l.4-.3v1.2M138.3 24.2h.8M153.1 23.4h.7l-.7 .8h.7M126.2 79.8l-.3 .1a.87 .87 0 0 0 0 1.2l.3-.1 .2-.4-.3-.3h-.2l-.3 .3M51 97.3l.4-.2 .3 .4-.8 .9h.8M64.5 97.7l.2-.1h.3v.8M65 97.8l.2-.2h.3l.1 .8M140.4 80.3h.7l-.7 .8h.7" fill="none" stroke="#840084" stroke-width=".18"/>
<g fill="#ffffc2" stroke="#ffffc2" stroke-width=".18">
<path d="M82.5 104.4h50.8v71.1h-50.8z"/>
<path d="M38.1 24.4h10.2v15.2h-10.2z"/>
<path d="M105.4 24.4h15.2v15.2h-15.2z"/>
<path d="M229.9 44.7h22.8v38.1h-22.8z"/>
</g>
<g fill="#840000" stroke="#840000" stroke-width=".25">
<path d="M42.7 30.7h.7v.8h-.7z"/>
<path d="M43.8 29.2l1.3 .6-1.3 .7z"/>
<circle cx="39.4" cy="29.8" r=".63"/>
<circle cx="42.5" cy="28.6" r=".38"/>
</g>
<g fill="#840000" stroke="#840000" stroke-width=".18">
<path d="M38.9 26.4h2.5l-.3 .8h-2z"/>
<path d="M214.6 133.1l1-.5-.5 1z"/>
<path d="M214.6 115.1l.5-.6 .5 1.1z"/>
<circle cx="143" cy="30.7" r=".25"/>
<circle cx="143" cy="33.5" r=".25"/>
<circle cx="113" cy="26.9" r=".25"/>
<circle cx="113" cy="29.5" r=".25"/>
<circle cx="119.4" cy="32" r=".25"/>
<circle cx="106.7" cy="32" r=".25"/>
<circle cx="113" cy="34.5" r=".25"/>
<circle cx="113" cy="37.1" r=".25"/>
</g>
<g fill="none" stroke="#0000c2" stroke-width=".18" stroke-dasharray=".4 .4">
<path d="M139.7 143.8v31.7M142.2 156.5h3.8M146 143.8h-6.3M27.9 169.2h20.4M48.3 169.2v20.3M53.3 169.2h20.4M73.7 169.2v20.3M139.7 175.5h10.2M142.2 169.2v-12.7M149.9 169.2h-7.7M27.9 189.5v-20.3M48.3 189.5h-20.4"/>
<path d="M53.3 189.5v-20.3M73.7 189.5h-20.4"/>
</g>
<path d="M177.8 12.9v152.4M12.7 63.7h165.1" fill="none" stroke="#0000c2" stroke-width=".25" stroke-dasharray=".6 .6"/>
<g fill="none" stroke="#008400" stroke-width=".18">
<path d="M50.8 34.5h48.3v8.9h11.4v-1.2M50.8 26.9h50.8v5.1h1.3M62.2 26.9v16.5M110.5 21.8v-1.2h-11.4v11.4h-48.3M115.6 21.8v-1.2h16.5v8.9h8.9M123.2 32h1.3M141 34.5h-8.9v8.9h-16.5v-1.2M151.1 34.5h14M151.1 29.5h14M205.7 30.7h35.6v10.2M207 30.7v1.3M207 39.6v1.3"/>
<path d="M215.9 30.7v33h10.2M224.8 38.3v1.3M238.8 30.7v10.2M238.8 33.3h6.3M241.3 39.6h3.8M252.7 39.6h5.1M252.7 33.3h5.1M40.6 42.2h2.6M41.9 42.2v1.2M62.2 42.2h19.1M62.2 51v1.3M74.9 42.2v1.2"/>
<path d="M74.9 51v1.3M203.2 56.1h22.9M224.8 47.2v3.8h-21.6M224.8 48.5h1.3M256.5 58.7h7.7M256.5 56.1h7.7M256.5 53.6h16.5M102.9 71.4v30.4M105.4 71.4v30.4M107.9 71.4v30.4M120.6 71.4v2.5M129.5 71.4h-29.2v30.4"/>
<path d="M137.2 71.4h19M146 71.4v1.2M205.7 71.4h20.4M226.1 73.9h-3.9v6.4h-31.7M226.1 76.4h-1.3v6.4h-34.3M256.5 63.7h16.5M256.5 79h5.1v1.3M261.6 75.2v1.2h-5.1M26.7 89.1h1.2M35.6 89.1h26.6M38.1 95.5h1.3M44.4 89.1v2.6"/>
<path d="M44.4 99.3v2.5M86.4 80.3h2.5M86.4 86.6h2.5M86.4 93h2.5M86.4 99.3h2.5M96.5 80.3h11.4M96.5 86.6h8.9M96.5 93h6.4M96.5 99.3h3.8M113 94.2h5.1M115.6 89.1v12.7M120.6 81.5v1.3"/>
<path d="M125.7 94.2h3.8M146 80.3v1.2M146 89.1v2.6M146 99.3v1.3M156.2 89.1h-43.2v12.7M241.3 86.6h2.5M242.6 86.6v1.3M25.4 119.6v1.3M26.7 101.8h1.2M35.6 119.6v1.3M35.6 101.8h26.6M55.9 115.8h3.8"/>
<path d="M55.9 110.7h3.8M67.3 110.7h7.6v5.1h-7.6M74.9 113.3h2.6v3.8h2.5M115.6 100.6h2.5M125.7 100.6h3.8M135.9 117.1h19M135.9 119.6h19M184.1 113.3h21.6M201.9 113.3v16.5h14M215.9 118.4h-11.4v16.5M215.9 108.2h50.8M228.6 113.3h1.3"/>
<path d="M228.6 108.2v8.9h2.5M238.8 117.1h1.2M240 113.3v5.1M251.5 108.2v1.3M251.5 117.1v1.3M256.5 108.2v1.3M256.5 117.1v1.3M25.4 128.5v1.3h54.6M35.6 128.5v1.3M62.2 124.7h17.8M62.2 137.4h2.6M62.2 122.2h17.8"/>
<path d="M62.2 132.3h17.8M72.4 137.4h7.6M135.9 124.7h16.5M135.9 137.4h16.5M135.9 129.8h29.2M135.9 132.3h29.2M184.1 134.9h21.6M215.9 139.9h50.8M228.6 139.9v8.9h2.5M25.4 143.8h1.3M25.4 150.1h1.3M34.3 143.8h1.3v8.8h44.4"/>
<path d="M34.3 150.1h1.3M45.7 142.5h1.3M45.7 148.8h1.3M54.6 142.5h1.3v7.6h24.1M54.6 148.8h1.3M62.2 142.5h17.8M62.2 145h17.8M66 159v10.2M135.9 142.5h10.1M135.9 155.2h10.1M135.9 145h10.1M135.9 157.7h10.1"/>
<path d="M153.7 142.5h7.6v2.5h-7.6M153.7 155.2h7.6v2.5h-7.6M161.3 156.5h1.3M161.3 143.8h1.3M228.6 145h1.3M238.8 148.8h1.2M240 145v5.1M35.6 176.8v1.2M40.6 166.6v2.6M40.6 176.8v1.2M40.6 167.9h39.4M61 176.8v1.2"/>
<path d="M66 176.8v1.2M66 165.3h14M80 160.3h-44.4v8.9M80 162.8h-19v6.4M107.9 178v1.3"/>
</g>
<path d="M81.3 41.5h.6l.6 .7-.6 .6h-.6zM264.2 58h.6l.6 .7-.6 .6h-.6zM264.8 55.5h.6v1.3h-.6l-.6-.7zM55.2 110.1h.7v1.3h-.7l-.6-.7zM154.9 117.1l.7-.6 .6 .6-.6 .6zM154.9 119.6l.7-.6 .6 .6-.6 .7zM266.7 107.6h.6l.7 .6-.7 .6h-.6zM266.7 139.3h.6l.7 .6-.7 .7h-.6z" fill="none" stroke="#848400" stroke-width=".25"/>
<path d="M34.7 16.3v1.3M35.3 16.3l-.4 .1-.2 .3M245 16.3l.4 1.9 .4-1.4 .4 1.4 .4-1.9M247.3 16.9v1.3M247.9 16.9l-.4 .1-.2 .3M248.5 17.1a.52 .52 0 0 1 .9 .2v.6a.51 .51 0 0 1-.5 .3 .51 .51 0 0 1-.5-.3zM250.1 16.9l.4 1.3 .5-1.3M251.6 17.6l.9-.2-.1-.4-.5-.1-.3 .3 .1 .9 .2 .1 .5-.1M253.3 16.9v1.3M253.9 16.9l-.4 .1-.2 .3M25.8 68.7l.8-.2a.45 .45 0 0 0 .2-.4 .45 .45 0 0 0-.4-.4h-.6v1.9h.7a.5 .5 0 0 0 .4-.5 .5 .5 0 0 0-.5-.4" fill="none" stroke="#0000c2" stroke-width=".38"/>
<g fill="none" stroke="#0000c2" stroke-width=".18">
<path d="M218.5 22.3h1.5M220.1 20.2l.7 1.9 .6-1.9M222.4 20.1l-.5 1.4h1.2M222.9 20.8v1.3M54.1 73.5h1.5M56.6 72.5a.46 .46 0 0 1 .5-.2 .46 .46 0 0 1 .3 .3 1.09 1.09 0 0 1-.4 1.6h-.2a1.15 1.15 0 0 1-.2-1.7zM58.2 72.8l.6-.5v1.9M58.2 74.2h1.1M61 72.3h-.9l-.1 .9 .3-.2 .6 .1 .2 .3-.1 .6-.2 .2h-.5l-.3-.2M62.2 73.1l-.4-.4 .1-.2 .3-.2a.63 .63 0 0 1 .7 .3l-.2 .4-.8 .3-.1 .5 .4 .4a.63 .63 0 0 0 .7-.4v-.3l-.3-.4M157.6 170.6l-.4-.1-.3 .3 .1 .5h.6M157.6 170.1v1.3"/>
<path d="M158.1 171.2v.2M163.7 168h-.7v.7l.2-.2 .4 .1 .1 .6-.2 .1-.5-.1M164.2 168.4l.4-.4v1.3M164.2 169.3h.7M165.4 174.4h.7l-.4 .5 .4 .1v.4l-.2 .3-.5-.2M165.5 177.3l.6-.1-.1-.3h-.3l-.2 .2v.6h.5M165.7 168l-.3 .9h.8M166 168.5v.8M167.2 176.9h-.4l-.3 .2 .2 .6h.5M167.2 176.4v1.3M167.6 174.9l.2-.1 .4 .1v.5l-.1 .2-.3 .1-.2-.2zM167.8 177.6v.1"/>
<path d="M168.8 174.8v.9M169.2 174.8l-.4 .3M224.3 160.4h-.6l-.1 .6 .2-.1 .5 .1v.6l-.2 .1-.5-.1M225 160.5l.1-.1a.67 .67 0 0 1 .5 .7 .67 .67 0 0 1-.5 .6l-.1-.1-.1-.4zM227.6 160.9h-.3l-.3 .2 .2 .5h.4M227.6 160.4v1.3M227.8 163l.2-.1 .4 .1v.5l-.1 .2h-.3l-.2-.1zM228.2 161.3l.6-.1-.1-.3h-.3l-.2 .1v.6h.5M229 163l.2-.1 .2 .1 .1 .7M229 162.9v.8M229.2 160.9l.3 .8 .3-.8M230 163.3l.7-.1-.1-.2-.4-.1-.2 .2 .1 .6h.5"/>
<path d="M230.3 160.4v.1M230.3 160.9v.8M231.2 163l.2-.1 .3 .1v.7M231.2 162.9v.8M231.4 160.9h-.3l-.3 .2 .2 .5h.4M231.9 161.3l.6-.1v-.3h-.4l-.2 .1 .1 .6h.5M232.2 162.9h.5M232.4 162.5v1.1l.3 .1M233.5 160.9h-.3l-.2 .1 .1 .2 .4 .1v.3h-.5M234 163.1h.5M234.6 162.5h-.6v1.2h.6M235.2 163.7v-1.2l.4 .9 .4-.9v1.2"/>
<path d="M236.7 163.1h.7M236.7 162.5v1.2M237.4 162.5v1.2M237.8 162.5h.8l-.4 .5 .4 .1-.1 .6h-.5l-.2-.1M239.2 163.6v.1M43 186.2l.5-.1v-.3h-.4l-.1 .1v.7h.5M44.6 185.8h-.3l-.3 .2 .1 .6h.5M44.6 185.3v1.3M68.1 187.1l.4-.1 .2 .3-.1 .5h-.5M68.3 185v.8M68.7 185l-.4 .2M68.9 185h.5"/>
<path d="M69.1 184.6v1l.3 .2M69.2 186.6v1.1l.2 .2M69.8 187.4l.7-.1-.1-.2-.4-.1-.2 .2 .1 .6h.5M70.7 184.7l.5-.1 .2 .3v.2l-.8 .7h.8"/>
</g>
<g fill="#008400" stroke="#008400" stroke-width=".25">
<circle cx="146.1" cy="89.1" r=".51"/>
<circle cx="35.6" cy="150.1" r=".51"/>
<circle cx="207" cy="30.7" r=".51"/>
<circle cx="161.3" cy="143.8" r=".51"/>
<circle cx="161.3" cy="156.5" r=".51"/>
<circle cx="242.6" cy="86.6" r=".51"/>
<circle cx="55.9" cy="148.8" r=".51"/>
<circle cx="240" cy="148.8" r=".51"/>
<circle cx="100.3" cy="99.3" r=".51"/>
<circle cx="224.8" cy="48.5" r=".51"/>
<circle cx="35.6" cy="129.8" r=".51"/>
<circle cx="201.9" cy="113.3" r=".51"/>
<circle cx="215.9" cy="30.7" r=".51"/>
<circle cx="44.5" cy="101.8" r=".51"/>
<circle cx="240" cy="117.1" r=".51"/>
<circle cx="102.9" cy="71.4" r=".51"/>
<circle cx="108" cy="80.3" r=".51"/>
<circle cx="228.6" cy="113.3" r=".51"/>
<circle cx="228.6" cy="139.9" r=".51"/>
<circle cx="105.4" cy="71.4" r=".51"/>
<circle cx="108" cy="71.4" r=".51"/>
<circle cx="228.6" cy="108.2" r=".51"/>
<circle cx="228.6" cy="145" r=".51"/>
<circle cx="120.7" cy="71.4" r=".51"/>
<circle cx="62.2" cy="42.2" r=".51"/>
<circle cx="62.2" cy="26.9" r=".51"/>
<circle cx="74.9" cy="42.2" r=".51"/>
<circle cx="41.9" cy="42.2" r=".51"/>
<circle cx="204.5" cy="134.9" r=".51"/>
<circle cx="129.5" cy="71.4" r=".51"/>
<circle cx="115.6" cy="89.1" r=".51"/>
<circle cx="238.8" cy="33.3" r=".51"/>
<circle cx="241.3" cy="39.6" r=".51"/>
<circle cx="115.6" cy="100.6" r=".51"/>
<circle cx="113" cy="94.2" r=".51"/>
<circle cx="238.8" cy="30.7" r=".51"/>
<circle cx="66" cy="165.3" r=".51"/>
<circle cx="256.5" cy="108.2" r=".51"/>
<circle cx="102.9" cy="93" r=".51"/>
<circle cx="105.4" cy="86.6" r=".51"/>
<circle cx="251.5" cy="108.2" r=".51"/>
<circle cx="40.6" cy="167.9" r=".51"/>
<circle cx="74.9" cy="113.3" r=".51"/>
<circle cx="146.1" cy="71.4" r=".51"/>
<circle cx="44.5" cy="89.1" r=".51"/>
</g>
<g fill="none" stroke="#000084" stroke-width=".18">
<path d="M50.2 36.5l1.2 1.2M51.4 36.5l-1.2 1.2M225.5 58.1l1.2 1.2M226.7 58.1l-1.2 1.2M255.9 47.9l1.2 1.2M255.9 50.4l1.2 1.3M257.1 47.9l-1.2 1.2M257.1 50.4l-1.2 1.3M255.9 70.8l1.2 1.2M255.9 73.3l1.2 1.2M255.9 60.6l1.2 1.2M255.9 65.7l1.2 1.2"/>
<path d="M257.1 70.8l-1.2 1.2M257.1 73.3l-1.2 1.2M257.1 60.6l-1.2 1.2M257.1 65.7l-1.2 1.2M37.5 94.9l1.2 1.2M38.7 94.9l-1.2 1.2M48.9 94.9l1.2 1.2M50.1 94.9l-1.2 1.2M135.3 134.3l1.2 1.2M135.3 121.6l1.2 1.2M136.5 134.3l-1.2 1.2M136.5 121.6l-1.2 1.2"/>
<path d="M135.3 147l1.2 1.2M135.3 149.5l1.2 1.2M135.3 159.7l1.2 1.2M136.5 147l-1.2 1.2M136.5 149.5l-1.2 1.2M136.5 159.7l-1.2 1.2M135.3 162.2l1.2 1.2M136.5 162.2l-1.2 1.2"/>
</g>
<use href="#words"/>
</svg>
